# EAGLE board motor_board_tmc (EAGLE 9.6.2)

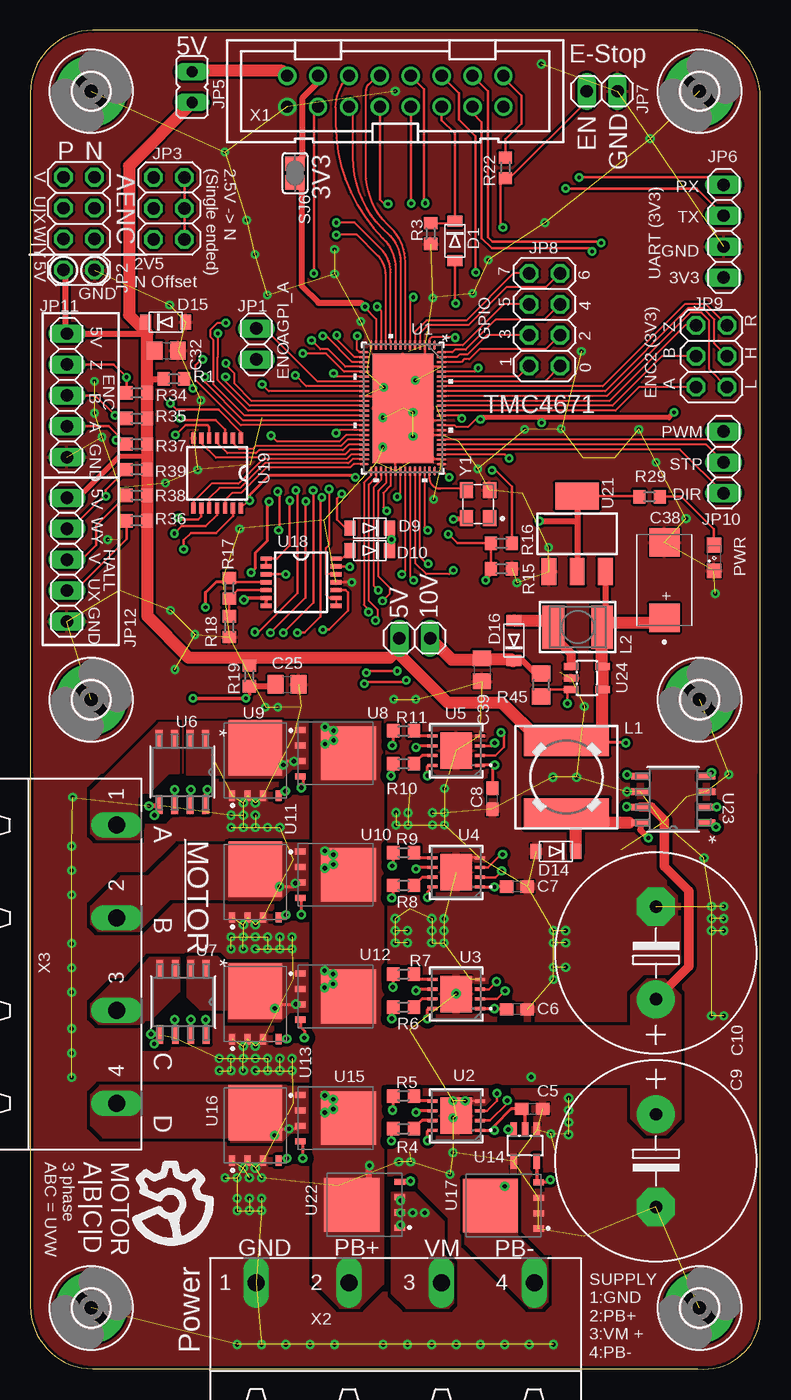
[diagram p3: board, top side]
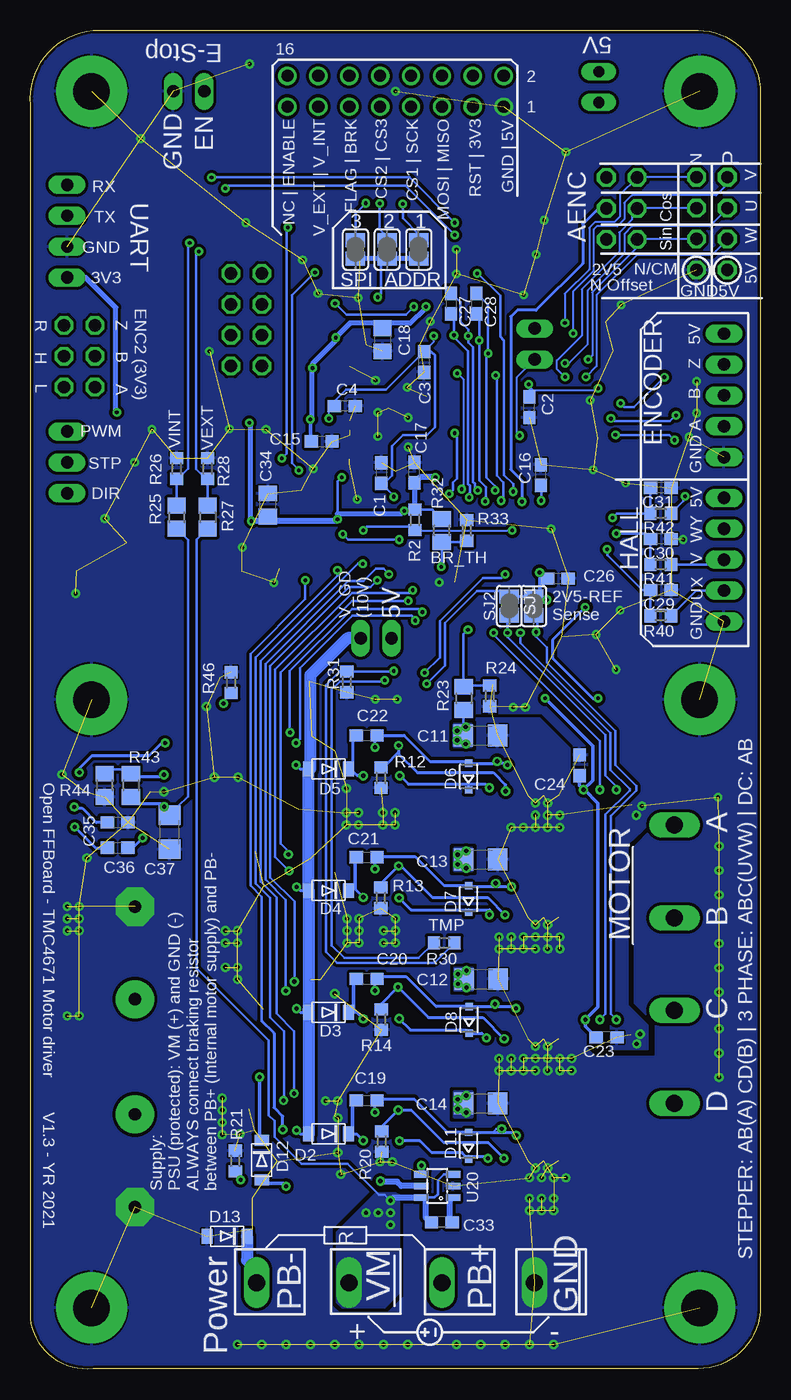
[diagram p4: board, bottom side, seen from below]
Size 60.02 x 110.03 mm. Coordinates in mm from the lower left corner, seen from the top.
Outline: 0,104.91 0,5.15 arc90 5.12,0.03 54.88,0.03 arc90 60,4.15 60,103.91 arc90 54.88,110.03 5.12,110.03 arc90 0,104.91
Copper layers (1*16): Top 0.035mm / dielectric 1.5mm / Bottom 0.035mm
Design rules "jlcpcb *": minimum track width 5mil, minimum drill 0.3mm, track to track 8mil, track to pad 8mil, pad to pad 8mil, via to via 8mil, smd to smd 5mil, copper to edge 0.2mm, drill to drill 8mil, minimum pad ring 10mil, minimum via ring 8mil, stop-mask expansion 4mil, vias tented up to drill 0.4mm, thermal gap 6mil

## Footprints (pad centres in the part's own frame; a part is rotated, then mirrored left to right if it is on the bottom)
C0603 = smd 1.1 x 1: 1 -0.85,0; 2 0.85,0
E7,5-16 = drill 1.016 pad 3.15: + -3.81,0 | drill 1.016 pad 3.15 octagon: - 3.81,0
C1206 = smd 1.6 x 1.8: 1 -1.4,0; 2 1.4,0
C0805 = smd 1.3 x 1.5: 1 -0.95,0; 2 0.95,0
CAPPM7343X310N = smd 2.31 x 2.52: 1 -3.1,0; 2 3.1,0
SOD-123FL = smd 0.91 x 1.22: A 1.637,0; C -1.637,0
SOD323-R = smd 0.6 x 0.6: A 1.1,0; C -1.1,0
3,0-PAD = drill 3 pad 5.842: B3,0 0,0
1X02 = drill 1.016 long: 1 -1.27,0; 2 1.27,0
2X04 = drill 1.016 octagon: 1 -3.81,-1.27; 2 -3.81,1.27; 3 -1.27,-1.27; 4 -1.27,1.27; 5 1.27,-1.27; 6 1.27,1.27; 7 3.81,-1.27; 8 3.81,1.27
2X03 = drill 1.016 octagon: 1 -2.54,-1.27; 2 -2.54,1.27; 3 0,-1.27; 4 0,1.27; 5 2.54,-1.27; 6 2.54,1.27
JP1 = drill 0.914 long: 1 0,-1.27; 2 0,1.27
1X04 = drill 1.016 long: 1 -3.81,0; 2 -1.27,0; 3 1.27,0; 4 3.81,0
1X03 = drill 1.016 long: 1 -2.54,0; 2 0,0; 3 2.54,0
1X05 = drill 1.016 long: 1 -5.08,0; 2 -2.54,0; 3 0,0; 4 2.54,0; 5 5.08,0
8MMINDUCTOR = smd 2.5 x 7: 1 -3,0; 2 3,0
L4532P = smd 1.8 x 3.6: 1 -2,0; 2 2,0
SML0805 = smd 1.2 x 1.2: A 1.05,0; C -1.05,0
R0603 = smd 1 x 1.1: 1 -0.85,0; 2 0.85,0
R0805 = smd 1.3 x 1.5: 1 -0.95,0; 2 0.95,0
SJ = smd 1.168 x 1.6: 1 -0.762,0; 2 0.762,0
QFN76_10P5X6P5 = smd 0.152 x 0.755: 1 -2.6,-5.173; 2 -2.2,-5.173; 3 -1.8,-5.173; 4 -1.4,-5.173; 5 -1,-5.173; 6 -0.6,-5.173; 7 -0.2,-5.173; 8 0.2,-5.173; 9 0.6,-5.173; 10 1,-5.173; 11 1.4,-5.173; 12 1.8,-5.173; 13 2.2,-5.173; 14 2.6,-5.173; 39 2.6,5.173; 40 2.2,5.173; 41 1.8,5.173; 42 1.4,5.173; 43 1,5.173; 44 0.6,5.173; 45 0.2,5.173; 46 -0.2,5.173; 47 -0.6,5.173; 48 -1,5.173; 49 -1.4,5.173; 50 -1.8,5.173; 51 -2.2,5.173; 52 -2.6,5.173 | smd 0.755 x 0.152: 15 3.179,-4.6; 16 3.179,-4.2; 17 3.179,-3.8; 18 3.179,-3.4; 19 3.179,-3; 20 3.179,-2.6; 21 3.179,-2.2; 22 3.179,-1.8; 23 3.179,-1.4; 24 3.179,-1; 25 3.179,-0.6; 26 3.179,-0.2; 27 3.179,0.2; 28 3.179,0.6; 29 3.179,1; 30 3.179,1.4; 31 3.179,1.8; 32 3.179,2.2; 33 3.179,2.6; 34 3.179,3; 35 3.179,3.4; 36 3.179,3.8; 37 3.179,4.2; 38 3.179,4.6; 53 -3.179,4.6; 54 -3.179,4.2; 55 -3.179,3.8; 56 -3.179,3.4; 57 -3.179,3; 58 -3.179,2.6; 59 -3.179,2.2; 60 -3.179,1.8; 61 -3.179,1.4; 62 -3.179,1; 63 -3.179,0.6; 64 -3.179,0.2; 65 -3.179,-0.2; 66 -3.179,-0.6; 67 -3.179,-1; 68 -3.179,-1.4; 69 -3.179,-1.8; 70 -3.179,-2.2; 71 -3.179,-2.6; 72 -3.179,-3; 73 -3.179,-3.4; 74 -3.179,-3.8; 75 -3.179,-4.2; 76 -3.179,-4.6 | smd 5.004 x 8.992: 77 0,0
SDC08A = smd 0.254 x 0.813: 1 -1.2,-1.943; 2 -0.4,-1.943; 3 0.4,-1.943; 4 1.2,-1.943; 5 1.2,1.943; 6 0.4,1.943; 7 -0.4,1.943; 8 -1.2,1.943 | smd 2.997 x 2.591: 9 0,0
SOIC8_D_TEX = smd 1.46 x 0.559: 1 -2.724,1.905; 2 -2.724,0.635; 3 -2.724,-0.635; 4 -2.724,-1.905; 5 2.724,-1.905; 6 2.724,-0.635; 7 2.724,0.635; 8 2.724,1.905
MOSFET_BSC093N04LSGATMA1 = smd 0.5 x 0.85: 1 -1.905,-2.9; 2 -0.635,-2.9; 3 0.635,-2.9; 4 1.905,-2.9 | smd 4.41 x 4.55: 5 0,1.05
SOT23-5L = smd 0.55 x 1.2: 1 -0.95,-1.3; 2 0,-1.3; 3 0.95,-1.3; 4 0.95,1.3; 5 -0.95,1.3
TSSOP14 = smd 0.9 x 0.35: 1 -2.875,1.95; 2 -2.875,1.3; 3 -2.875,0.65; 4 -2.875,0; 5 -2.875,-0.65; 6 -2.875,-1.3; 7 -2.875,-1.95; 8 2.875,-1.95; 9 2.875,-1.3; 10 2.875,-0.65; 11 2.875,0; 12 2.875,0.65; 13 2.875,1.3; 14 2.875,1.95
SOT23-6 = smd 0.55 x 1.2: 1 -0.95,-1.3; 2 0,-1.3; 3 0.95,-1.3; 4 0.95,1.3; 5 0,1.3; 6 -0.95,1.3
SOT223 = smd 1.219 x 2.235: 1 -2.311,-3.099; 2 0,-3.099; 3 2.311,-3.099 | smd 3.6 x 2.2: 4 0,3.099
21-0041B_8_MXM = smd 0.543 x 1.455: 1 -1.905,-2.721; 2 -0.635,-2.721; 3 0.635,-2.721; 4 1.905,-2.721; 5 1.905,2.721; 6 0.635,2.721; 7 -0.635,2.721; 8 -1.905,2.721
PAK100/2500-16 = drill 1 pad 1.422: 1 -8.89,-1.27; 2 -8.89,1.27; 3 -6.35,-1.27; 4 -6.35,1.27; 5 -3.81,-1.27; 6 -3.81,1.27; 7 -1.27,-1.27; 8 -1.27,1.27; 9 1.27,-1.27; 10 1.27,1.27; 11 3.81,-1.27; 12 3.81,1.27; 13 6.35,-1.27; 14 6.35,1.27; 15 8.89,-1.27; 16 8.89,1.27
GMSTBA4 = drill 1.397 long: 1 -11.43,5.08; 2 -3.81,5.08; 3 3.81,5.08; 4 11.43,5.08
ECS-327KE-TR = smd 1.3 x 1.1: 1 -1.15,-0.95; 2 1.15,-0.95; 3 1.15,0.95; 4 -1.15,0.95

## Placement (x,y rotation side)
C1  100nF  [C0603]  31.18,73.65 270 bottom
C2  100nF  [C0603]  19,79.05 90 bottom
C3  100nF  [C0603]  27.65,82.78 90 bottom
C4  100nF  [C0603]  34.17,79.15 180 bottom
C5  100nF  [C0603]  41.25,21.38 180 top
C6  100nF  [C0603]  40,29.58 180 top
C7  100nF  [C0603]  40,39.65 180 top
C8  100nF  [C0603]  37.98,46.88 90 top
C9  680µF  [E7,5-16]  51.42,17.13 270 top
C10  680µF  [E7,5-16]  51.42,34.2 90 top
C11  1µF  [C1206]  23.02,52.08 0 bottom
C12  1µF  [C1206]  22.98,32.05 0 bottom
C13  1µF  [C1206]  23,41.88 0 bottom
C14  1µF  [C1206]  23,21.83 0 bottom
C15  100nF  [C0603]  36.08,76.25 0 bottom
C16  100nF  [C0603]  18.05,73.48 90 bottom
C17  100nF  [C0603]  28.45,73.68 90 bottom
C18  4.7µF  [C0805]  31.07,84.6 270 bottom
C19  100nF  [C0603]  32.38,22.08 0 bottom
C20  100nF  [C0603]  32.38,32.08 0 bottom
C21  100nF  [C0603]  32.38,42.08 0 bottom
C22  100nF  [C0603]  32.38,52.08 0 bottom
C23  100nF  [C0603]  12.65,27.28 180 bottom
C24  100nF  [C0603]  14.88,49.63 90 bottom
C25  4.7µF  [C0805]  21.1,56.28 0 top
C26  100n  [C0603]  16.65,64.98 0 bottom
C27  1n  [C0603]  25.45,87.58 270 bottom
C28  1n  [C0603]  23.35,87.58 270 bottom
C29  1n  [C0603]  8.2,64.03 180 bottom
C30  1n  [C0603]  8.2,68.23 180 bottom
C31  1n  [C0603]  8.2,72.43 180 bottom
C32  4.7µF  [C0805]  11.18,83.7 0 top
C33  100nF  [C0603]  26.2,12.08 180 bottom
C34  4.7µF  [C0805]  40.5,71.03 90 bottom
C35  100nF  [C0603]  52.85,44.93 180 bottom
C36  100nF  [C0603]  52.85,42.85 0 bottom
C37  1µF  [C1206]  48.58,44.13 90 bottom
C38  593D476X0016D2TE3  [CAPPM7343X310N]  52.12,64.85 90 top
C39  4.7µF  [C0805]  37.12,57.48 270 top
D1  LV low drop  [SOD-123FL]  34.9,92.73 270 top
D2  HV >100V  [SOD-123FL]  35.5,19.33 180 bottom
D3  HV >100V  [SOD-123FL]  35.5,29.33 180 bottom
D4  HV >100V  [SOD-123FL]  35.5,39.33 180 bottom
D5  HV >100V  [SOD-123FL]  35.5,49.33 180 bottom
D6  BZX384-XXX  [SOD323-R]  24,48.7 90 bottom
D7  BZX384-XXX  [SOD323-R]  24,38.63 90 bottom
D8  BZX384-XXX  [SOD323-R]  23.95,28.7 90 bottom
D9  LV low drop  [SOD-123FL]  27.9,69.13 180 top
D10  LV low drop  [SOD-123FL]  27.9,67.28 180 top
D11  BZX384-XXX  [SOD323-R]  24,18.35 90 bottom
D12  HV >100V  [SOD-123FL]  41,17.18 270 bottom
D13  Zener 65V (MMSZ5265BT1G)  [SOD-123FL]  43.85,10.93 180 bottom
D14  HV >100V  [SOD-123FL]  43.2,42.55 180 top
D15  5.6V zener  [SOD-123FL]  11.12,86.05 0 top
D16  LV low drop  [SOD-123FL]  39.75,59.88 90 top
H1  MOUNT-PAD-ROUND3.0  [3,0-PAD]  55,5.03 0 top
H2  MOUNT-PAD-ROUND3.0  [3,0-PAD]  5,5.03 0 top
H3  MOUNT-PAD-ROUND3.0  [3,0-PAD]  55,105.03 0 top
H4  MOUNT-PAD-ROUND3.0  [3,0-PAD]  55,55.03 0 top
H5  MOUNT-PAD-ROUND3.0  [3,0-PAD]  5,105.03 0 top
H6  MOUNT-PAD-ROUND3.0  [3,0-PAD]  5,55.03 0 top
JP1  [1X02]  18.57,84.25 90 top
JP2  [2X04]  4,94.15 90 top
JP3  [2X03]  11.4,95.4 270 top
JP4  V_DRV  [1X02]  31.6,60.08 180 top
JP5  5V  [JP1]  13.3,105.38 180 top
JP6  [1X04]  57,93.53 270 top
JP7  [1X02]  47,105.03 180 top
JP8  [2X04]  42.27,86.25 90 top
JP9  [2X03]  56,83.25 90 top
JP10  [1X03]  57,74.53 270 top
JP11  [1X05]  3,80.03 270 top
JP12  [1X05]  3,66.53 270 top
L1  220µH  [8MMINDUCTOR]  44.08,48.65 90 top
L2  10µH  [L4532P]  45,60.98 180 top
LED1  Green  [SML0805]  56.2,66.68 90 top
R1  2.2  [R0603]  11.8,81.38 180 top
R2  10k  [R0603]  28.4,69.8 90 bottom
R3  10k  [R0603]  32.9,93.33 90 top
R4  2.2  [R0603]  30.68,19.75 0 top
R5  2.2  [R0603]  30.68,22.45 0 top
R6  2.2  [R0603]  30.68,29.75 0 top
R7  2.2  [R0603]  30.68,32.45 0 top
R8  2.2  [R0603]  30.68,39.75 0 top
R9  2.2  [R0603]  30.68,42.45 0 top
R10  2.2  [R0603]  30.68,49.75 0 top
R11  2.2  [R0603]  30.68,52.45 0 top
R12  33k  [R0603]  31.2,48.6 90 bottom
R13  33k  [R0603]  31.23,38.73 90 bottom
R14  33k  [R0603]  31.18,28.73 90 bottom
R15  10k  [R0603]  38.73,65.78 180 top
R16  1.5k  [R0603]  38.73,67.88 180 top
R17  10k  [R0603]  16.35,64.18 90 top
R18  10k  [R0603]  16.35,61.03 90 top
R19  2.2  [R0603]  18,56.98 90 top
R20  33k  [R0603]  31.15,18.7 90 bottom
R21  33k  [R0603]  43.17,17.1 270 bottom
R22  1.5k  [R0603]  39.05,98.73 90 top
R23  71.5k  [R0805]  24.4,55.13 270 bottom
R24  1.5k  [R0603]  22.25,55.33 90 bottom
R25  294k  [R0805]  48,70.03 270 bottom
R26  10k  [R0603]  48,74.03 270 bottom
R27  294k  [R0805]  45.45,70.03 270 bottom
R28  10k  [R0603]  45.45,74.03 270 bottom
R29  1.5k  [R0603]  50.9,71.7 180 top
R30  10k thermistor  [R0603]  26,35.03 180 bottom
R31  1.5k  [R0603]  34,56.48 90 bottom
R32  71.5k  [R0805]  26.2,68.93 90 bottom
R33  47k  [R0603]  24.15,68.93 270 bottom
R34  4.7k  [R0603]  8.75,80.23 0 top
R35  4.7k  [R0603]  8.75,78.13 0 top
R36  4.7k  [R0603]  8.75,69.73 0 top
R37  4.7k  [R0603]  8.75,76.03 0 top
R38  4.7k  [R0603]  8.75,71.83 0 top
R39  4.7k  [R0603]  8.75,73.93 0 top
R40  1.5k  [R0603]  8.2,61.93 0 bottom
R41  1.5k  [R0603]  8.2,66.13 0 bottom
R42  1.5k  [R0603]  8.2,70.33 0 bottom
R43  294k  [R0805]  51.75,47.98 270 bottom
R44  71.5k  [R0805]  53.92,47.98 270 bottom
R45  71.5k  [R0805]  42,56.23 90 top
R46  10k  [R0603]  43.52,56.43 270 bottom
SJ1  [SJ]  20.65,62.73 270 bottom
SJ2  [SJ]  18.65,62.73 270 bottom
SJ3  [SJ]  28.1,92.03 270 bottom
SJ4  [SJ]  30.7,92.03 270 bottom
SJ5  [SJ]  33.3,92.03 270 bottom
SJ6  3.3V  [SJ]  21.75,98.3 270 top
U1  TMC4671  [QFN76_10P5X6P5]  30.62,78.98 180 top
U2  LM5109BSD  [SDC08A]  35,20.83 90 top
U3  LM5109BSD  [SDC08A]  35,30.83 90 top
U4  LM5109BSD  [SDC08A]  35,40.83 90 top
U5  LM5109BSD  [SDC08A]  35,50.83 90 top
U6  TMCS1100  [SOIC8_D_TEX]  12.5,49.08 270 top
U7  TMCS1100  [SOIC8_D_TEX]  12.55,30.18 270 top
U8  BSC030N08NS5ATMA1  [MOSFET_BSC093N04LSGATMA1]  25.1,50.63 270 top
U9  BSC030N08NS5ATMA1  [MOSFET_BSC093N04LSGATMA1]  18.5,50.03 0 top
U10  BSC030N08NS5ATMA1  [MOSFET_BSC093N04LSGATMA1]  25.1,40.63 270 top
U11  BSC030N08NS5ATMA1  [MOSFET_BSC093N04LSGATMA1]  18.5,40.03 0 top
U12  BSC030N08NS5ATMA1  [MOSFET_BSC093N04LSGATMA1]  25.1,30.63 270 top
U13  BSC030N08NS5ATMA1  [MOSFET_BSC093N04LSGATMA1]  18.5,30.03 0 top
U14  MCP14XX  [SOT23-5L]  40.67,18.38 180 top
U15  BSC030N08NS5ATMA1  [MOSFET_BSC093N04LSGATMA1]  25.1,20.63 270 top
U16  BSC030N08NS5ATMA1  [MOSFET_BSC093N04LSGATMA1]  18.5,20.03 0 top
U17  BSC030N08NS5ATMA1  [MOSFET_BSC093N04LSGATMA1]  38.88,13.45 90 top
U18  MCP6004  [TSSOP14]  22.25,64.68 0 top
U19  74LV17APWJ  [TSSOP14]  15.35,73.63 270 top
U20  LM74700-Q1  [SOT23-6]  26.57,15.05 90 bottom
U21  [SOT223]  44.95,68.65 0 top
U22  BSC030N08NS5ATMA1  [MOSFET_BSC093N04LSGATMA1]  27.48,13.5 90 top
U23  MAX5033BASA+T  [21-0041B_8_MXM]  52.85,46.83 90 top
U24  AP3012KTR-G1  [SOT23-5L]  45.75,56.8 270 top
X1  2516-  [PAK100/2500-16]  30,105.03 0 top
X2  GMSTBA4  [GMSTBA4]  30,2.03 0 top
X3  GMSTBA4  [GMSTBA4]  2,33.28 270 top
Y1  25MHz  [ECS-327KE-TR]  36.8,71.1 90 top

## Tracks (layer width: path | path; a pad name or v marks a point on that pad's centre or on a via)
2.5V_REF  (via drill 0.3, 0.35)
  Top 0.2: JP3.2 JP3.4 JP3.6 | v27.45,56.33 27.6,56.48 30.75,56.48 v30.9,56.63
  Top 0.254: v18.15,65.48 18.47,65.8 18.47,67.08 19.47,68.07 19.47,71.16 v19.62,71.31
  Top 0.305: U18.7 U18.6 17.7,63.38 v17.55,63.23
  Bottom 0.2: SJ2.1 SJ1.1 21.1,63.94 23.32,63.94 25.95,61.31 25.95,57.83 v27.45,56.33 | SJ2.1 18.39,63.23 | R30.2 28.1,33.78 34.2,33.78 35.25,34.83 35.25,55.86 34.58,56.52 31,56.52 v30.9,56.63 | 18.15,63.99 SJ2.1 | C26.1 18,65.48 v18.15,65.48
  Bottom 0.254: JP3.4 12.82,95.55 13.16,95.55 14.61,94.11 14.61,90.88 18.46,87.03 20,87.03 20.52,86.5 20.52,73.94 19.62,73.04 v19.62,71.31
  Bottom 0.305: 18.39,63.23 v17.55,63.23 | v18.15,65.48 18.15,63.99
2.5V_REF_A  (via drill 0.3, 0.35)
  Top 0.152: U1.17 26.44,82.78 24.29,84.93 v24.02,84.93
  Top 0.2: 11.87,47.61 v11.85,47.63 | v23.24,72.23 23.29,72.18 23.29,63.01 v20.8,60.53
  Top 0.254: U6.6 11.87,47.61
  Bottom 0.2: v11.85,47.63 11.85,47.88 12.75,48.78 12.75,52.13 20.8,60.18 v20.8,60.53 20.8,61.81 SJ1.2 | v23.24,72.23 23.49,72.48 23.49,72.77 23.64,72.92 23.64,83.99 24.02,84.37 v24.02,84.93 24.02,85.45 24.65,86.07 24.65,87.7 25.37,88.43 C27.1
2.5V_REF_C  (via drill 0.3, 0.35)
  Top 0.152: U1.19 25.8,81.98 24.3,83.47 v22.4,83.47
  Top 0.2: v21.82,72.22 21.97,72.07 21.97,63.8 18.75,60.58 v18.45,60.58
  Top 0.254: U7.6 11.91,28.66 v11.85,28.73
  Bottom 0.2: v11.85,28.73 12.3,29.18 12.3,45.45 10.2,47.55 10.2,47.93 11.94,49.67 11.94,52.46 17.55,58.07 17.55,59.33 18.45,60.23 v18.45,60.58 18.35,60.68 18.35,61.66 SJ2.2 | v21.82,72.22 21.82,72.56 22.54,73.28 22.54,83.34 v22.4,83.47 22.4,87.48 C28.1
2.5V_REF_RAW
  Top 0.2: U18.5 17.05,64.03 R17.1 R18.2
5V_ADC  (via drill 0.3)
  Top 0.152: U1.23 19.6,80.38 v19.05,80.93
  Top 0.2: R1.1 12.65,81.32 v13.34,80.62
  Bottom 0.152: C2.2 19,80.88 v19.05,80.93 19.05,80.78 18.74,80.47 13.49,80.47 v13.34,80.62
5V_SENSE  (via drill 0.3, 0.35)
  Top 0.2: U18.4 16.35,64.68 R17.2 16.05,64.73
  Top 0.254: 16.05,64.73 15.3,64.73 14.4,63.83 v14.4,62.63 | v14.55,47.63 14.4,47.48 U6.8 | v14.4,28.73 14.46,28.67 U7.8
  Top 0.3: v13.35,55.13 v17.7,55.13 18,55.43 R19.1
  Top 0.5: R19.1 20,56.13 C25.1
  Bottom 0.2: v14.55,47.63 14.47,47.63
  Bottom 0.254: v13.35,55.13 13.8,55.13 17.1,58.43 17.1,59.93 v14.4,62.63
  Bottom 0.3: v17.7,55.13 13.8,51.23 13.8,48.38 v14.55,47.63 14.88,47.95 C24.1 | C23.2 14.4,28.18 v14.4,28.73 13.35,29.78 13.35,46.5 14.47,47.63
+3V3  (via drill 0.3, 0.35)
  Top 0.152: U1.52 33.25,73.78 33.95,73.78 v34.42,73.3 | U1.43 29.62,72.6 29.02,72 29.02,70.83 v29.3,70.55 | U1.13 28.42,86.3 27.5,87.22 v27.5,87.33 | v34.92,84.78 34.92,84.83 33,84.83 32.82,84.65 U1.2 | v36.83,82.28 36.52,81.98 U1.72 | v37,78.05 36.6,78.05 35.99,77.44 35,77.44 34.87,77.58 U1.61
  Top 0.2: U21.4 50,71.75 R29.2 | U19.14 17.93,71.38 v18.02,71.38
  Top 0.254: v26.73,73.3 26.57,73.45 19.64,73.45 18.02,71.83 v18.02,71.38
  Top 0.4: Y1.4 35.75,69.85 v34.77,69.85 | v52.92,78.63 52.5,78.2 42.05,78.2 | 42.05,78.2 37.15,78.2 v37,78.05 | v42.02,77.78 42.02,78.18 42.05,78.2
  Top 0.5: v27.5,87.33 27.18,87.65 23.68,87.65 22.3,89.03 22.3,96.99 SJ6.2 | U21.4 44.95,69.7 | v41.85,69.7 44.95,69.7 | 44.95,69.7 U21.2
  Bottom 0.2: v29.3,70.55 29.2,70.65 R2.2 26.98,70.65 R32.2 | C34.1 40.88,69.7 v41.85,69.7 | v34.42,73.3 34.77,72.95 v34.77,69.85 | C15.1 37,76.33 | C16.1 18.02,72.6 v18.02,71.38
  Bottom 0.3: v27.5,87.33 27.6,87.23 | 36.91,78.15 v37,78.05 37,76.33 | v34.77,69.85 34.77,69.73
  Bottom 0.4: v34.77,69.85 34.77,70.3 29.55,70.3 v29.3,70.55 28.93,70.55 28.45,71.03 C17.1 | 27.6,87.23 27.6,87.13 28.77,85.95 31.07,85.95 | 36.91,78.15 36.91,82.2 v36.83,82.28 36.83,82.63 34.92,84.53 v34.92,84.78 33.73,85.98 31.07,85.98 31.07,85.95 | v52.92,78.63 53,78.7 53,87.25 55.47,89.72 JP6.4 | v42.02,77.78 41.98,77.73 41.98,69.83 v41.85,69.7 | C18.1 31.07,85.95
  Bottom 0.5: v41.85,69.7 41.83,69.73 34.77,69.73 | v26.73,73.3 27.98,73.3 C17.1
+5V  (via drill 0.35)
  Top 0.152: R34.2 9.6,80.88
  Top 0.2: 56,48.84 55.9,48.73 U23.4 | v48.95,51.45 48.91,51.49 | 47.54,51.49 47.38,51.65 L1.2 | D15.C 9.49,85.51 9.35,85.38 | 18,58.46 R19.2
  Top 0.254: v56,49.03 56,48.84 | 48.91,51.49 47.54,51.49
  Top 0.4: JP12.1 3.88,71.61 7.33,75.05 9.6,75.05
  Top 0.5: 9.6,85.13 9.58,85.11 JP11.1 2.88,85.23 2.88,90.2 JP2.2 | U24.4 47,55.8 | 47,52.03 46.62,51.65 L1.2 | 9.6,81.03 9.95,81.38 R1.2
  Top 0.508: U21.3 47.26,61.24 L2.1
  Top 0.8: U24.5 47,57.8
  Top 1: U24.4 U24.5 | 9.6,83.08 9.6,81.03 R34.2 R35.2 R37.2 9.6,75.05 R39.2 R38.2 R36.2 9.6,61.88 13.01,58.46 18,58.46 29.54,58.46 30.33,59.25 JP4.2 30.33,58.75 34.33,54.75 38.77,54.75 41.88,51.65 L1.2 | 9.6,83.08 9.6,85.13 9.35,85.38 8.1,86.63 8.1,98.91 JP5.2 | 47,55.8 47,52.03 | C32.1 9.6,83.08 | C38.1 51.67,61.3 47.33,61.3 L2.1 47,57.8
  Bottom 0.254: v56,49.03 56,49.38 54.95,50.43 50.27,50.43 49.25,51.45 v48.95,51.45
AENC_UX  (via drill 0.3)
  Top 0.15: 18.2,79.58 16.75,81.03 16.75,81.85 16.07,82.53 v16.07,82.68
  Top 0.152: U1.25 18.2,79.58
  Bottom 0.15: 14.22,88.65 14.22,84.2 15.75,82.68 v16.07,82.68
  Bottom 0.152: 14.22,88.65 11.19,91.69 11.19,93.29 10.56,93.93 4.17,93.93 2.73,95.37 JP2.6
AENC_UX_N  (via drill 0.3)
  Top 0.15: U1.26 18.02,79.18 16.05,81.15 v16.05,81.55
  Bottom 0.152: v16.05,81.55 16.1,81.55 16.75,82.2 16.75,82.9 14.7,84.95 14.7,88.75 11.61,91.84 11.61,93.42 10.58,94.45 10.58,94.95 JP3.3 10.11,95.42 JP2.5
AENC_VN  (via drill 0.3)
  Top 0.15: U1.27 17.91,78.78
  Top 0.152: 17.91,78.78 15.39,81.29 15.39,83.17 15.41,83.18 v15.41,85.13
  Bottom 0.152: 2.72,97.41 3.65,96.48 10.57,96.48 11.2,95.85 11.2,94.5 11.78,93.92 13.46,93.92 13.72,93.65 13.72,90.23 15.41,88.55 v15.41,85.13
  Bottom 0.2: JP2.8 2.72,97.95 2.72,97.41
AENC_VN_N  (via drill 0.3)
  Top 0.15: U1.28 17.62,78.38 15.04,80.96
  Top 0.152: v16.08,85.98 15.36,85.98 14.78,85.4 14.78,84.87 15.04,84.61 15.04,80.96
  Bottom 0.152: v16.08,85.98 16.08,88.38 14.08,90.38 14.08,93.8 13.61,94.27 12.01,94.27 11.56,94.72 11.56,96.52 JP3.1 10.11,97.96 JP2.7
AENC_WY  (via drill 0.3)
  Top 0.15: U1.29 17.48,77.98 14.35,81.11 v14.35,81.55
  Bottom 0.152: v14.35,81.55 13.47,82.43 13.47,88.25 10.18,91.55 4,91.55 2.73,92.83 JP2.4
AENC_WY_N  (via drill 0.3)
  Top 0.15: U1.30 17.28,77.58 13.57,81.28 13.57,82.53
  Top 0.152: 13.57,82.53 14.03,82.98 v14.17,82.98
  Bottom 0.152: v14.17,82.98 13.83,83.31 13.83,88.5 10.13,92.2 JP3.5 10.11,92.88 JP2.3
AGPI_A
  Top 0.152: U1.21 23.6,81.18 19.25,85.52 JP1.2
AGPI_B  (via drill 0.3)
  Top 0.152: U1.22 22.68,80.78 v21.78,81.68
  Top 0.2: U18.2 U18.1 20.27,66.63 21.32,67.67 v21.32,71.38
  Bottom 0.2: v21.78,81.68 21.68,81.58 21.68,73.43 21.12,72.86 21.12,71.58 v21.32,71.38
BRAKE_CTRL  (via drill 0.3, 0.35)
  Top 0.2: D10.C 29.69,67.43 v29.69,68.18 29.69,69.15 29.56,69.15 D9.C | v34.35,68.63 35.1,67.88 R16.2 R15.2 37.88,65.28 v37.42,64.83
  Top 0.254: U14.3 v39.27,19.68
  Bottom 0.2: 41,28.63 41,38.82 41.92,39.73 41.92,58.79 37.42,63.28 v37.42,64.83 | v34.35,68.63 33.9,68.18 v29.69,68.18
  Bottom 0.254: v39.27,19.68 39.27,20.78 40,21.5 40,27.63 41,28.63
BRAKE_CTRL_EXT  (via drill 0.3)
  Top 0.2: X1.12 35.25,104.86 35.25,102.68 36.6,101.33 36.6,90.18 v36.62,90.15 | R16.1 39.58,72.55 38.25,73.88 v37.95,73.88
  Bottom 0.2: v36.62,90.15 38.52,88.26 38.52,74.45 v37.95,73.88
BRAKE_CTRL_TMC  (via drill 0.3)
  Top 0.152: U1.31 25.38,77.18 v25.12,76.93
  Top 0.2: v25.6,71.95 25.2,71.55 25.2,69.83 25.9,69.13 D9.A
  Bottom 0.2: v25.12,76.93 24.95,76.75 24.95,73.2 25.3,72.85 25.3,72.25 v25.6,71.95
BRAKE_GATE  (via drill 0.35)
  Top 0.254: v42.75,15.55 42.55,15.36 U17.4
  Top 0.3: U17.4 41.65,15.48 41.65,17.05 U14.5
  Bottom 0.2: R21.2 42.75,16.25 v42.75,15.55
BRAKE_RES_COMP
  Top 0.152: D10.A 25.61,66.63 U18.14
BRAKE_RES_TH  (via drill 0.3)
  Top 0.2: U18.13 26.2,65.98 v26.25,65.93
  Bottom 0.2: R33.2 24.25,67.98 R32.1 26.2,65.98 v26.25,65.93
C_HS_A  (via drill 0.3, 0.35)
  Top 0.152: U1.39 28.02,73.45 27.42,72.85 27.42,62.8 27.79,62.43 v27.79,62.23
  Top 0.2: U5.2 38.23,50.43 38.92,51.13 38.92,52.08 v38.67,52.33
  Bottom 0.2: v38.67,52.33 38.7,52.35 38.7,57.37 33.59,62.48 28.12,62.48 27.87,62.23 v27.79,62.23
C_HS_B  (via drill 0.3, 0.35)
  Top 0.152: U1.41 28.82,73.05 28.22,72.45 28.22,64.41 v28.6,64.03
  Top 0.2: U4.2 38.23,40.43 v38.75,40.95
  Bottom 0.2: v38.75,40.95 39.9,42.1 39.9,57.5 33.6,63.8 28.82,63.8 v28.6,64.03
C_HS_C  (via drill 0.3, 0.35)
  Top 0.152: U1.46 30.8,73.78 30.8,65.58 v30.55,65.33
  Top 0.2: U3.2 38.38,30.43 v39.02,31.08
  Bottom 0.2: v39.02,31.08 39.02,38.55 40.71,40.23 40.71,57.97 33.91,64.76 32.64,64.76 31.62,65.78 31,65.78 v30.55,65.33
C_HS_D  (via drill 0.3, 0.35)
  Top 0.152: v34.77,65.65 34.45,65.33 32.55,65.33 31.62,66.26 U1.48
  Top 0.2: U2.2 37.77,20.43 39.2,21.85 v39.2,22.08
  Bottom 0.2: v39.2,22.08 39.15,22.13 39.15,27.75 40.33,28.93 40.33,38.71 41.51,39.9 41.51,58.49 34.77,65.23 v34.77,65.65
C_LS_A  (via drill 0.3, 0.35)
  Top 0.152: U1.40 28.42,73.3 27.82,72.7 27.82,63.13 28.52,62.43 28.52,61.68 v28.38,61.53
  Top 0.2: U5.3 37.95,51.23 v38.17,51.45
  Bottom 0.2: v38.17,51.45 37.85,51.78 37.85,57.63 33.52,61.95 28.68,61.95 28.38,61.65 v28.38,61.53
C_LS_B  (via drill 0.3, 0.35)
  Top 0.152: U1.42 29.22,72.8 28.62,72.2 28.62,65.13 29.56,64.19 29.56,63.74 v28.95,63.13
  Top 0.2: U4.3 37.62,41.23 38.7,42.3 v38.83,42.3
  Bottom 0.2: v38.83,42.3 38.83,42.58 39.45,43.2 39.45,57.25 33.57,63.13 v28.95,63.13
C_LS_C  (via drill 0.3, 0.35)
  Top 0.152: U1.47 31.22,65.11 v31.5,64.83
  Top 0.2: U3.3 37.7,31.23 v38.33,31.85
  Bottom 0.2: v38.33,31.85 38.33,38.42 40.3,40.4 40.3,57.8 33.82,64.28 32.05,64.28 v31.5,64.83
C_LS_D  (via drill 0.3, 0.35)
  Top 0.152: U1.49 32,73.78 32,66.78 32.58,66.2 v32.7,66.2
  Top 0.2: v38.35,22.65 38.35,22.05 37.52,21.23 U2.3
  Bottom 0.2: v38.35,22.65 38.35,27.78 39.8,29.23 39.8,38.76 41.11,40.07 41.11,58.19 33.1,66.2 v32.7,66.2
CLK_25M
  Top 0.152: Y1.3 35.75,72.35 33.7,72.35 arc-90 32.82,73.23 U1.51
CS1  (via drill 0.3)
  Top 0.2: X1.7 28.73,96.12 29.1,95.75 v29.4,95.75
  Bottom 0.2: SJ3.1 28.1,93.29 29.4,94.59 v29.4,95.75
CS2  (via drill 0.3)
  Top 0.2: X1.9 31.27,95.84 v31.3,95.81
  Bottom 0.2: v31.3,95.81 31.3,93.71 30.7,93.11 SJ4.1
CS3  (via drill 0.3)
  Top 0.2: X1.10 32.38,105.19 32.38,95.8 32.42,95.8 v32.45,95.83
  Bottom 0.2: SJ5.1 33.3,94.98 v32.45,95.83
CS_TMC  (via drill 0.3)
  Top 0.152: 31.43,88.1 31.22,87.9 U1.6
  Top 0.2: v31.48,88.1 31.43,88.1
  Bottom 0.2: v31.48,88.1 31.2,88.38 31.2,90.76 SJ4.2
  Bottom 0.4: SJ3.2 SJ4.2 SJ5.2
DIR
  Top 0.152: JP10.3 53.41,75.58 U1.56
ENABLE  (via drill 0.3)
  Top 0.152: 39.02,75.18 U1.55
  Top 0.2: v39.35,74.84 39.02,75.18 | v38.85,93.82 38.62,94.05 38.62,97.45 R22.1 39.4,97.88 45.73,104.21 JP7.2
  Bottom 0.2: v38.85,93.82 38.95,93.72 38.95,75.24 v39.35,74.84
ENC2_A
  Top 0.152: JP9.2 50.03,80.71 48.09,78.78 U1.64
ENC2_B
  Top 0.152: JP9.4 51.93,83.25 47.85,79.18 U1.65
ENC2_Z
  Top 0.152: JP9.6 53.83,85.79 47.62,79.58 U1.66
ENC_A
  Top 0.152: U1.35 26.26,75.58 25.85,75.17 18.98,75.17 18.73,74.91 15.26,74.91 14.05,76.12 U19.6
ENC_A_5V  (via drill 0.3)
  Top 0.152: v7.05,76.35 7.58,76.35 R37.1
  Top 0.2: R37.1 6.44,77.49 JP11.4 | U19.5 14.7,77.44 14.55,77.59 12.77,77.59 11.95,76.78 v11.93,76.78
  Bottom 0.2: v7.05,76.35 7.47,76.78 v11.93,76.78
ENC_B
  Top 0.152: U1.34 26.16,75.98 25.7,75.52 18.8,75.52 18.55,75.27 16.2,75.27 15.35,76.12 U19.4
ENC_B_5V  (via drill 0.3)
  Top 0.2: R35.1 7.22,78.13 v6.95,78.4 5.33,80.03 JP11.3 | U19.3 16,77.21 15.21,77.99 12.3,77.99 v12.3,78.13
  Bottom 0.2: v6.95,78.4 7.45,77.9 12.07,77.9 v12.3,78.13
ENC_Z
  Top 0.152: U1.33 26.05,76.38 25.55,75.88 18.53,75.88 18.27,75.62 17.15,75.62 16.65,76.12 U19.2
ENC_Z_5V  (via drill 0.3)
  Top 0.2: JP11.2 6.86,82.57 v7.9,81.53 R34.1 | U19.1 17.3,77.02 15.48,78.85 12.03,78.85 v11.5,79.38
  Bottom 0.2: v11.5,79.38 11.2,79.08 10.4,79.08 7.92,81.55 v7.9,81.53
ENO  (via drill 0.3)
  Top 0.152: U1.32 25.95,76.78 25.41,76.23 20.28,76.23 v19.79,76.73
  Bottom 0.152: JP1.1 20.05,81.51 20.05,76.99 v19.79,76.73
FLAG
  Top 0.152: R3.2 34.85,94.18 34.9,94.23 D1.C
  Top 0.2: X1.11 33.81,102.66 34.9,101.57 D1.C
G_HS_A  (via drill 0.35)
  Top 0.254: v22.27,47.78 22.48,47.78 22.48,48.45 U8.4 | R10.1 29.82,48.95 v29.65,48.78
  Bottom 0.2: D6.C 24,48.08
  Bottom 0.254: v22.27,47.78 22.57,48.08 24,48.08 28.95,48.08 v29.65,48.78
G_HS_B  (via drill 0.35)
  Top 0.254: v22.27,37.35 22.27,38.65 U10.4 | R8.1 29.82,38.85 v29.7,38.73
  Bottom 0.2: D7.C 24,37.75
  Bottom 0.254: 24,37.75 22.27,37.75 v22.27,37.35 | v29.7,38.73 28.73,37.75 24.23,37.75 D7.C
G_HS_C  (via drill 0.35)
  Top 0.254: U12.4 22.2,28.13 22.52,27.8 v22.52,27.23 | v29.7,28.8 29.82,28.93 R6.1
  Bottom 0.254: v22.52,27.23 22.9,27.6 D8.C 24.23,27.88 28.77,27.88 v29.7,28.8
G_HS_D  (via drill 0.35)
  Top 0.254: v22.4,17.33 22.4,18.52 U15.4 | v29.68,18.75 29.68,19.6 R4.1
  Bottom 0.2: D11.C 24,17.5
  Bottom 0.254: 24,17.5 22.45,17.5 22.4,17.45 v22.4,17.33 | D11.C 24.52,17.78 27.02,17.78 28,18.75 v29.68,18.75
G_LS_A  (via drill 0.35)
  Top 0.254: U9.4 20.57,47.13 v20.95,47.5 | R11.1 29.82,51.33 v29.75,51.25
  Bottom 0.152: R12.2 31.02,49.45 30.73,49.75
  Bottom 0.254: v20.95,47.5 20.95,48.01 21.97,49.03 28.21,49.03 29.75,50.58 | v29.75,51.25 29.75,50.58 | 29.75,50.58 29.82,50.65 30.73,49.75
G_LS_B  (via drill 0.35)
  Top 0.254: U11.4 20.8,37.13 v21,37.33 | R9.1 29.82,41.43 v29.75,41.35
  Bottom 0.152: R13.2 31.04,39.76 31.04,40.06
  Bottom 0.254: v21,37.33 22.43,38.75 26.95,38.75 29.55,41.35 v29.75,41.35 31.04,40.06
G_LS_C  (via drill 0.35)
  Top 0.254: U13.4 20.43,27.15 v21.07,27.15 | R7.1 29.82,31.42 v29.8,31.39
  Bottom 0.152: R14.2 31.18,30.02
  Bottom 0.254: v21.07,27.15 22.82,28.9 27.31,28.9 v29.8,31.39 31.18,30.02
G_LS_D  (via drill 0.35)
  Top 0.254: v21.1,17.33 20.61,17.33 U16.4 | R5.1 29.82,21.34 v29.77,21.29
  Bottom 0.152: R20.2 31.15,19.92
  Bottom 0.254: v21.1,17.33 22.4,18.63 26.05,18.63 28.72,21.29 v29.77,21.29 31.15,19.92
GND  (via drill 0.3, 0.35)  (275 unrouted)
  Top 0.152: 30.62,80.03 30.62,81.9 31.1,82.38 32.5,82.38 | 30.62,80.03 U1.77 | U1.24 29,79.98 | 29,79.98 30.57,79.98 30.62,80.03 | U1.54 33.25,74.78 31.5,76.52 | 31.42,76.78 31.59,76.61 31.5,76.52 | 31.42,76.78 30.62,77.58 30.62,78.03 | 30.62,78.03 U1.77 | U1.62 32.55,77.98 32.5,78.03 30.62,78.03 | U1.73 32.5,82.38 | U1.3 32.42,82.46 32.5,82.38 | U1.77 30,78.98 29,79.98 | U1.44 30.02,75.01 30,75.03 31.5,76.52 | U1.59 31.42,76.78
  Top 0.2: U2.4 36.92,22.05 v35.75,22.05 | U4.4 36.92,42.05 35.75,42.05 35,41.3 U4.9 | U5.4 36.92,52.05 | 36.16,32.03 35,30.87 U3.9 | U18.11 v26.43,64.68
  Top 0.4: v10.2,45.53 10.6,45.92 U6.5 10.51,46.44 10.35,46.28 v9.75,46.28 | v10.18,26.73 10.64,27.2 U7.5 10.57,27.53 v9.9,27.53
  other vias: 19.5,25.53 18.5,25.53 17.5,25.53 16.5,25.53 16.5,24.53 17.5,24.53 19.5,24.53 18.5,24.53 16,100.03 30,105.03 25,92.03 36.38,88.4 42.3,94.23 42,107.28 25,90.03 29.05,80.68 19,13.03 17,13.03 50.95,101.13 11.45,87.48 15.53,24.53 17.5,26.53 18.5,26.53 36.77,74 51.45,74.53 17.77,94.43 13.75,73.93 45.3,83.65 31.65,81.28 28.98,78.2 31.45,78.63 28.98,75.78 31.45,76.68 19,15.73 18,15.73 17,15.73 16,15.73 17.5,16.53 18.5,16.53 19.5,35.53 18.5,35.53 17.5,35.53 16.5,35.53 16.5,34.53 17.5,34.53 19.5,34.53 18.5,34.53 17.5,36.53 18.5,36.53 18.5,45.53 17.5,45.53 16.5,45.53 16.5,44.53 17.5,44.53 19.5,44.53 18.5,44.53 17.5,46.53 33.15,71.48 19,14.03 17,14.03 18,14.03 18,13.03 15.53,25.53 27.15,86.1 5.25,81.18 5.25,78.58 6.35,68.18 5.88,76.6 18.45,91.63 11.1,72.83 35,30.85 34.75,22.05 34.75,20.65 34,35.03 34,36.03 33,37.03 30,37.03 34,37.03 33,35.03 30,35.03 33,36.03 30,36.03 31,36.03 31,35.03 34.05,44.73 33.05,45.73 34.05,45.73 33.05,44.73 30.05,44.73 31.05,44.73 20.5,44.53 20.5,24.53 20.5,25.53 21.5,25.53 21.5,24.53 20.5,34.53 20.5,35.53 21.5,35.53 21.5,34.53 34.5,16 34.75,17.8 30.27,17.03 31.27,17.03 19.48,88.28 55.38,42 57.42,48.88 11.53,62.38 37.65,91.18 42.6,67.53 45.55,54.45 40,64.63 31.05,45.73 30.05,45.73 3.4,42.98 3.4,40.98 3.4,38.98 3.4,34.98 3.4,32.98 3.4,30.98 3.4,27.98 3.4,25.98 3.4,23.98 42.8,19.33 44,36.03 44,35.03 44,33.03 43,32.03 43,33.03 43,35.03 43,36.03 44.25,19.28 44.25,20.28 44.25,21.28 44.25,22.28 41,2.03 39,2.03 37,2.03 35,2.03 33,2.03 31,2.03 29,2.03 25,2.03 23,2.03 21,2.03 19,2.03 17,2.03 43,2.03 34.05,47.73 11.88,57.5 20.32,54.4 43.65,77.28 40.65,77.23 50.02,77.25 17.2,69.08 3.48,47 49.05,47.45 42.95,48.65 44.9,48.65 53.9,69.9 56.3,63.75 14,79.63 19.32,54.4 31.68,55.05 29.88,55.05 56,38.03 56,37.03 56,36.03 57,36.03 57,37.03 57,38.03 56,29.03 57,29.03 13.53,60.38 33.08,88.05 18.5,46.53
  pour Bottom (isolate 0.254, rank 6): 0,0.03 0,111.03 60,111.03 60,0.03
  pour Top (rank 6): 0,49 0,111.03 60,111.03 60,49
  pour Top (no thermals): 16.15,24.53 19.5,24.53 19.5,27.73 16.15,27.73
  pour Top (isolate 0.254, rank 6): 0,49.13 60,49.13 60,0.03 0,0.03
  pour Top (no thermals): 16.15,15.53 19.5,15.53 19.5,17.73 16.15,17.73
  pour Top (no thermals): 16.15,34.53 19.5,34.53 19.5,37.83 16.15,37.83
  pour Top (no thermals): 16.15,44.53 19.5,44.53 19.5,47.73 16.15,47.73
  pour Top (no thermals): 17,9.6 17,4.28 20,4.28 20,9.6
  pour Bottom (no thermals): 17,9.6 17,4.28 20,4.28 20,9.6
  pour Top (no thermals): 41,14.5 43,14.5 43,11.03 41,11.03
  pour Top (no thermals): 53.42,15.13 49.42,15.13 49.42,11.13 53.42,11.13
  pour Bottom (no thermals): 53.42,15.13 49.42,15.13 49.42,11.13 53.42,11.13
  pour Bottom (no thermals): 53.45,40.05 49.45,40.05 49.45,36.05 53.45,36.05
  pour Top (isolate 0.5, no thermals): 53.45,40.05 49.45,40.05 49.45,36.05 53.45,36.05
  pour Top (no thermals): 22,105.03 20,105.03 20,102.68 22,102.68
  pour Bottom (no thermals): 22,105.03 20,105.03 20,102.68 22,102.68
  cutout Top: 9,44.93 11.1,44.93 11.55,45.38 11.55,46.88 11.25,47.18 9.3,47.18 9,46.88
  cutout Bottom: 8.75,25.78 13.55,25.78 14.25,26.48 14.25,28.28 12.45,28.28 12.45,26.18 9.15,26.18 9.15,28.28 10.8,29.93 10.8,43.13 9,44.78 9,44.48 10.5,42.98 10.5,30.08 8.75,28.33
  cutout Bottom: 15.45,48.98 15.45,51.23 18,53.78 23.55,53.78 23.55,53.63 18.15,53.63 15.6,51.08 15.6,48.98
GND1
  cutout Top: 9.2,26.23 11.3,26.23 11.45,26.38 11.45,28.48 9.5,28.48 9.2,28.18
GPIO0
  Top 0.152: JP8.1 42.28,81.18 U1.70
GPIO1
  Top 0.152: JP8.2 40.14,81.58 U1.71
GPIO2
  Top 0.152: JP8.3 42.4,83.84 36.93,83.84 36.09,83 35.66,83 35.44,82.78 U1.74
GPIO3
  Top 0.152: JP8.4 37.53,84.98 35.95,83.39 35.28,83.39 35.07,83.18 U1.75
GPIO4
  Top 0.152: JP8.5 42.27,86.25 38.24,86.25 35.77,83.78 34.9,83.78 34.7,83.58 U1.76
GPIO5
  Top 0.152: JP8.6 38.93,87.52 35.55,84.14 U1.1
GPIO6
  Top 0.152: JP8.7 42.4,88.92 39.13,88.92 36.02,85.81 32.68,85.81 32.02,85.15 U1.4
GPIO7
  Top 0.152: JP8.8 39.72,90.06 35.84,86.19 32.55,86.19 31.62,85.25 U1.5
HALL_UX
  Top 0.152: U1.38 26.57,74.38 26.29,74.1 19.43,74.1 17.34,72.01 16.59,72.01 16,71.43 U19.12
HALL_UX_5V  (via drill 0.3)
  Top 0.2: U19.13 16.65,70.12 15.26,68.73 13.2,68.73 12.6,68.13 v12.6,67.38
  Bottom 0.2: R40.1 C29.2 9.7,64.03 12.6,66.93 v12.6,67.38
HALL_V
  Top 0.152: U1.37 26.46,74.78 26.14,74.45 19.28,74.45 17.25,72.42 15.54,72.42 14.7,71.58 U19.10
HALL_V_5V  (via drill 0.3)
  Top 0.2: U19.11 15.35,70.21 14.42,69.28 12.45,69.28 v11.85,68.68
  Bottom 0.2: R41.1 C30.2 9.5,68.68 v11.85,68.68
HALL_WY
  Top 0.152: U1.36 26.36,75.18 26,74.81 19.13,74.81 17.1,72.78 14.89,72.78 13.4,71.28 U19.8
HALL_WY_5V  (via drill 0.3)
  Top 0.2: U19.9 14.05,70.08 13.8,69.83 12.3,69.83 v12.15,69.98
  Bottom 0.2: 9.11,72.43 C31.2 R42.1 11.8,70.33 v12.15,69.98
INPUT_GATE  (via drill 0.35)
  Top 0.5: v31.25,15.45 31.2,15.41 U22.4
  Bottom 0.5: U20.5 29.52,15.05 29.88,15.4 31.2,15.4 v31.25,15.45
MISO
  Top 0.152: X1.6 arc45 25.1,103.67 25.1,102.35 arc45 29.01,92.92 arc-45 30.02,90.47 U1.9
MOSI
  Top 0.152: U1.8 30.42,91.05 arc45 29.55,93.14 28.95,93.75 arc-45 26.52,99.62 26.52,102.93 26.52,103.43 X1.5
MOT_A  (via drill 0.35)
  Top 0.152: 21.69,49.99 v21.65,49.95
  Top 0.2: U8.3 21.69,49.99
  Top 0.254: v21.65,49.95 21.1,49.95 v20.8,49.65 | U5.6 31.97,51.23 31.84,51.1 v31.69,51.1
  Bottom 0.152: C22.2 31.69,51.91 v31.69,51.1
  Bottom 0.2: 22,49.78 21.82,49.95 v21.65,49.95
  Bottom 0.254: v20.8,49.65 20.93,49.78 22,49.78 23.98,49.78 D6.A 24.15,49.95 27.18,49.95 29.3,52.08 31.43,52.08 31.69,51.81 v31.69,51.1
  pour Top (isolate 0.305, no thermals): 22.8,53.23 22.8,49.33 21.5,49.33 20.75,48.58 15.85,48.58 15.85,53.23
  pour Top (isolate 0.305, no thermals): 12.9,48.88 18.7,48.88 18.7,51.13 16.62,53.2 12.9,53.2
MOT_A_OUT
  pour Top (isolate 0.305, no thermals): 5,47.5 5,44.03 5.45,43.58 9,43.58 9,46.58 11.4,48.98 12.18,48.98 12.18,53.1 10.6,53.1
MOT_B  (via drill 0.35)
  Top 0.152: U10.3 21.84,39.99 v21.77,39.93
  Top 0.254: v20.48,39.65 21.66,39.65 22,39.99 U10.3 | U4.6 31.97,41.23 31.84,41.1 v31.69,41.1
  Bottom 0.152: C21.2 31.69,41.91 v31.69,41.1
  Bottom 0.2: v21.77,39.93 22,39.7 22,39.65
  Bottom 0.254: v31.69,41.1 31.69,41.81 31.43,42.08 28.35,42.08 26,39.73 D7.A 23.93,39.65 22,39.65 v20.48,39.65
  pour Top (isolate 0.305, no thermals): 22.8,43.23 22.8,39.35 21.32,39.35 20.5,38.53 16.32,38.53 16.32,43.23
  pour Top (isolate 0.305, no thermals): 5,38.03 5,36.6 5.58,36.03 8.9,36.03 11.5,38.63 20,38.63 20,43.03 12.25,43.03 9.7,40.48 7.45,40.48
MOT_C  (via drill 0.35)
  Top 0.254: v20.1,29.65 20.44,29.99 v21.82,29.99 U12.3 | U3.6 31.97,31.23 31.84,31.1 v31.69,31.1
  Bottom 0.152: C20.2 31.69,31.91 v31.69,31.1
  Bottom 0.2: 22,29.8 21.82,29.98 v21.82,29.99
  Bottom 0.254: v20.1,29.65 20.25,29.8 22,29.8 D8.A 26.68,29.8 29.1,32.23 31.27,32.23 31.69,31.81 v31.69,31.1
  pour Top (isolate 0.305, no thermals): 22.77,33.4 22.77,29.33 21.3,29.33 20.5,28.53 16.3,28.53 16.3,33.4
  pour Top (isolate 0.305, no thermals): 12.97,33.88 15.35,33.88 15.88,33.35 16.32,33.35 16.52,33.15 17.45,33.15 17.45,29.55 13.97,29.55 12.97,30.55
MOT_C_OUT
  pour Top (isolate 0.305, no thermals): 12.22,33.8 12.22,31.05 9.55,28.38 5.6,28.38 5,28.98 5,30.03 6.75,31.78 7.97,31.78 9.81,33.8
MOT_D  (via drill 0.35)
  Top 0.254: v20.07,19.2 20.61,19.74 v21.27,19.74 21.95,19.74 U15.3 | U2.6 31.97,21.23 31.84,21.1 v31.69,21.1
  Bottom 0.152: C19.2 31.69,21.91 v31.69,21.1
  Bottom 0.2: 22,19.45 21.71,19.74 v21.27,19.74
  Bottom 0.254: v20.07,19.2 20.32,19.45 22,19.45 D11.A 25.75,19.45 28.5,22.2 31.3,22.2 31.69,21.81 v31.69,21.1
  pour Top (isolate 0.305, no thermals): 22.8,23.23 22.8,19.4 21.38,19.4 20.6,18.63 16.5,18.63 16.5,23.23
  pour Top (isolate 0.305, no thermals): 21,19.03 6,19.03 5,20.03 5,22.53 5.75,23.28 21,23.28
N$1
  Top 0.2: R36.1 7.9,68.23 3.6,63.93 3.06,63.93 JP12.4
  Bottom 0.2: R40.2 5.29,63.99 JP12.4
N$3
  Top 0.2: R38.1 5.4,69.33 5.4,67.73 4.2,66.53 JP12.3
  Bottom 0.2: R41.2 3.4,66.13 JP12.3
N$4  (via drill 0.3)
  Top 0.152: v28.5,87.33 28.82,87.01 U1.12
  Top 0.2: D1.A 34.9,87.68 v34.98,87.6
  Bottom 0.2: v34.98,87.6 34.04,86.66 29.16,86.66 v28.5,87.33
N$5  (via drill 0.35)
  Top 0.2: v44.15,54.7 44.15,55.55 U24.3 42.58,55.85 R45.1
  Bottom 0.2: R46.2 44.15,54.95 v44.15,54.7
N$8
  Top 0.2: R29.1 53.52,71.7 56.2,69.03 LED1.A
N$12
  Top 0.5: D16.A 39.76,61.53
  Top 0.75: U24.1 44.45,58.8 43.17,60.08 43.17,60.8 L2.2
  Top 1: L2.2 42.45,61.53 39.76,61.53
N$13
  Top 0.254: U5.5 31.52,52.03 R11.2
N$15  (via drill 0.3)
  Top 0.2: R39.1 6.2,72.23 6.2,71.93 | v6.2,71.73 6.2,71.93 | 6.2,71.93 3.34,69.07 JP12.2
  Bottom 0.2: R42.2 6.35,71.33 6.35,71.58 v6.2,71.73
N$16  (via drill 0.35)
  Top 0.5: 49.2,44.9 49.23,44.92 U23.8 50.13,44.32 v50.8,43.65
  Top 0.8: 45.95,45.65 L1.1 | 46.7,44.9 46.63,44.97 45.95,45.65 | 45.95,45.65 45.67,45.93
  Top 1: 49.2,44.9 46.7,44.9 | D14.C 44.84,45.1 45.67,45.93
  Bottom 0.2: C36.2 51.6,42.85
  Bottom 0.254: v50.8,43.65 51.6,42.85
N$17
  Top 0.2: X1.16 38.89,106.14 40.35,104.68 40.35,102.38 39.05,101.08 R22.2
N$18  (via drill 0.35)
  Top 0.254: v32.65,48.78 32.65,49.57 32.71,49.63 U5.8
  Bottom 0.152: C22.1 33.33,52.08
  Bottom 0.25: v32.65,48.78 33.15,48.78 33.7,49.33 D5.C
  Bottom 0.254: 33.33,52.08 33.52,51.88 33.52,49.66 D5.C
N$19  (via drill 0.35)
  Top 0.2: U23.1 56.16,44.92
  Top 0.254: v56.38,44.55 56.38,44.7 56.16,44.92
  Bottom 0.254: v56.38,44.55 54.67,42.85 C36.1
N$20
  Top 0.5: SJ6.1 22.38,99.69 22.38,104.5 23.65,105.78 X1.4
N$21  (via drill 0.35)
  Top 0.2: 50.11,48.75 U23.5
  Top 0.254: 50.11,48.75 49.15,48.75 v49.05,48.85
  Bottom 0.2: R44.1 53.55,49.3 51.73,49.3 51.75,49.28 R43.1 51.55,48.73
  Bottom 0.254: 51.55,48.73 49.17,48.73 v49.05,48.85
N$23
  Top 1: X1.2 20.71,106.7 13.35,106.7 JP5.1
N$24
  Bottom 0.152: C33.1 25.25,12.08
  Bottom 0.5: U20.1 25.55,14.1 25.55,12.38 25.25,12.08
N$25  (via drill 0.35)
  Top 0.2: 56.42,46.12 56.4,46.09 | 55.67,46.09 U23.2
  Top 0.254: v56.42,46.2 56.42,46.12 | 56.4,46.09 55.67,46.09
  Bottom 0.254: C35.2 54.6,44.93 55.77,46.1 56.33,46.1 v56.42,46.2
N$27
  Top 0.254: U5.7 32.2,50.43 R10.2
N$28  (via drill 0.35)
  Top 0.254: U4.8 32.65,39.22 v32.65,38.78
  Bottom 0.152: C21.1 33.33,42.08
  Bottom 0.254: v32.65,38.78 33.33,39.45 33.45,39.45
  Bottom 0.3: 33.33,42.08 33.35,42.05 33.35,39.55 33.45,39.45 33.58,39.33 D4.C
N$29
  Top 0.254: U4.5 31.52,42.03 R9.2
N$30
  Top 0.254: U4.7 32.2,40.43 R8.2
N$31  (via drill 0.35)
  Top 0.254: v32.65,18.78 32.65,19.57 32.71,19.63 U2.8
  Bottom 0.152: C19.1 33.33,22.08
  Bottom 0.254: v32.65,18.78 33.2,19.33 D2.C
  Bottom 0.3: 33.33,22.08 33.55,21.85 33.55,19.33 D2.C
N$32
  Top 0.254: U2.5 31.52,22.03 R5.2
N$33
  Top 0.254: U2.7 32.2,20.43 R4.2
N$34  (via drill 0.35)
  Top 0.254: v32.65,28.78 32.65,29.57 32.71,29.63 U3.8
  Bottom 0.152: C20.1 33.33,32.08
  Bottom 0.254: v32.65,28.78 33.2,29.33 D3.C
  Bottom 0.3: 33.33,32.08 33.48,31.93 33.48,29.33 D3.C
N$35
  Top 0.254: U3.5 31.52,32.03 R7.2
N$36
  Top 0.254: U3.7 32.2,30.43 R6.2
PWM_I
  Top 0.152: JP10.1 56.31,76.38 U1.58
REF_H
  Top 0.152: JP9.3 56.23,84.29 56.23,86.27 55.31,87.19 54.07,87.19 47.26,80.38 U1.68
REF_L
  Top 0.152: JP9.1 55.8,82.18 55.8,86.19 55.16,86.83 54.26,86.83 47.4,79.98 U1.67
REF_R
  Top 0.152: JP9.5 55.52,87.54 53.81,87.54 47.04,80.78 U1.69
RES_FET  (via drill 0.35)
  Top 0.254: v39,15.03 37.83,13.85 U17.5
  Bottom 0.254: D12.A 41,15.25
  Bottom 0.305: 41,15.25 39.23,15.25 v39,15.03
  Bottom 1: D13.C 42.21,8.98 41.43,8.19 X2.4
  pour Top (isolate 0.305, no thermals): 42.5,9.03 42.5,5.53 42,5.03 41.02,5.03 35.75,10.3 35.75,15.6 40,15.6 40,11.03 42,9.03
RESET  (via drill 0.3)
  Top 0.152: U1.50 32.4,73.78 32.4,69.19 v32.66,68.93
  Top 0.2: X1.3 23.32,103.43 23.32,90.08 v23.3,90.05 | v20.32,72.13 20.5,72.13 20.5,68.93 v20.4,68.93
  Bottom 0.152: R2.1 28.38,68.93 v20.4,68.93
  Bottom 0.2: v32.66,68.93 32.34,69.25 28.7,69.25 R2.1 | v20.32,72.13 20.32,72.73 21.07,73.48 21.07,84.53 21.4,84.85 21.4,88.23 23.23,90.05 v23.3,90.05
SCK
  Top 0.152: U1.7 30.82,91.02 arc45 29.7,93.73 29.36,94.07 arc-45 27.57,98.37 27.57,105.07 arc-45 27.79,105.58 28.5,106.3 X1.8
SENSE_A  (via drill 0.3, 0.35)
  Top 0.152: v25.2,84.98 25.2,84.61 26.64,83.18 U1.16
  Top 0.2: v23.94,71.65 23.85,71.56 23.85,61.84 22.54,60.53 v21.94,60.53
  Top 0.254: U6.7 13.13,47.56 v13.2,47.63
  Bottom 0.2: v23.94,71.65 23.94,72.01 23.89,72.05 23.89,72.6 24.05,72.75 24.05,83.67 25.2,84.83 v25.2,84.98 25.2,86.48 C27.2 | v13.2,47.63 13.2,51.64 21.94,60.38 v21.94,60.53
SENSE_C  (via drill 0.3, 0.35)
  Top 0.152: U1.18 25.9,82.38 24.45,83.83 23.84,83.83 v23.11,84.55
  Top 0.2: 13.19,28.71 v13.2,28.73 | v19.74,60.53 22.63,63.42 v22.63,71.33
  Top 0.254: U7.7 13.19,28.71
  Bottom 0.2: v13.2,28.73 12.75,29.18 12.75,45.57 10.76,47.57 10.76,47.67 12.35,49.26 12.35,52.29 19.74,59.69 v19.74,60.53 | v22.63,71.33 22.58,71.38 22.58,72.5 23.11,73.03 v23.11,84.55 23.11,86.49 C28.2
STEP
  Top 0.152: JP10.2 55.55,75.98 U1.57
TH_FET  (via drill 0.3)
  Top 0.2: U18.3 v21,65.33 | v27.61,57.24 27.75,57.38 v30.15,57.38
  Bottom 0.2: v21,65.33 21.3,65.03 22.8,65.03 26.35,61.48 26.35,58.5 v27.61,57.24 | R30.1 26.8,33.38 34.8,33.38 35.7,34.28 35.7,56.23 34.6,57.33 R31.2 30.2,57.33 v30.15,57.38
UART_RX  (via drill 0.3)
  Top 0.152: U1.10 29.62,90.15 arc45 28.84,92.04 26.65,94.23 v25.15,94.23
  Top 0.2: JP6.1 56.38,97.95 v45.12,97.95
  Bottom 0.2: v25.15,94.23 28.88,97.95 v45.12,97.95
UART_TX  (via drill 0.3)
  Top 0.152: U1.11 29.22,89.91 arc45 28.55,91.52 26.85,93.23 v25.15,93.23
  Top 0.2: JP6.2 54.77,97.03 v44,97.03
  Bottom 0.2: v44,97.03 43.77,97.26 29.18,97.26 v25.15,93.23
V+  (via drill 0.35)
  Top 0.4: U23.7 49.06,46.19 v49.02,46.23
  Top 0.5: v27.88,16.73 27.8,16.65 27.8,14.88 U22.5
  Top 0.8: C10.+ 54.12,33.09 54.12,39.3 52.12,41.3 52.12,45.12 51.05,46.19 U23.7
  Bottom 0.2: R43.2 51.2,46.48 | v49.02,46.23 47.9,46.23 47.08,47.05 47.08,68.13 48,69.05 R25.2 | R23.2 24.4,52.1 C11.1
  Bottom 0.254: 51.2,46.48 49.27,46.48 v49.02,46.23
  Bottom 0.305: v41.17,24 41.17,18.99 D12.C
  Bottom 0.5: v27.88,16.73 U20.4 | v49.02,46.23 49.02,45.98 C37.2
  other vias: 24.9,22.18 24.9,21.38 24.2,21.08 24.2,22.48 24.88,32.45 24.88,31.65 24.18,31.35 24.18,32.75 24.9,42.28 24.9,41.48 24.2,41.18 24.2,42.58 24.93,52.48 24.93,51.68 24.23,51.38 24.23,52.78
  pour Bottom (isolate 0.305, no thermals): 23.73,51.18 23.73,52.98 25.23,52.98 25.23,51.18
  pour Bottom (isolate 0.305, no thermals): 23.7,20.73 23.7,22.8 25.2,22.8 25.2,20.73
  pour Bottom (isolate 0.305, no thermals): 23.68,31.15 23.68,32.95 25.18,32.95 25.18,31.15
  pour Bottom (isolate 0.305, no thermals): 23.7,40.98 23.7,42.78 25.2,42.78 25.2,40.98
  pour Top (isolate 0.5, no thermals): 23.27,53.18 29,53.18 29,7.03 27,5.03 25.48,5.03 23.27,7.23
  pour Top (isolate 0.4, no thermals): 53.42,20.55 53.42,30.73 52.17,31.98 50.67,31.98 49.42,30.73 49.42,28.13 28,28.13 28,23.48 49.42,23.48 49.42,20.6 50.67,19.35 52.23,19.35
V_EXT  (via drill 0.3)
  Top 0.2: X1.13 36.35,103.25 37.1,102.5 37.1,92.95 37.92,92.13 45.9,92.13 v46.17,91.85
  Bottom 0.2: 45.73,73.3 45.5,73.08 45.45,73.08 | 45.73,73.3 46.4,73.98 46.4,91.63 v46.17,91.85 | R27.1 45.45,73.08 | 45.45,73.08 R28.2 45.58,73.3 45.73,73.3
V_GD  (via drill 0.35)
  Top 0.2: R45.2 41.75,56.93
  Top 0.254: U5.1 36.97,49.65 v38.17,49.65 38.08,49.65 37.98,49.55 C8.2 | U4.1 v38.15,39.63 38.17,39.65 C7.2 | U3.1 v38.15,29.63 38.2,29.58 C6.2 | U2.1 v38.15,19.63 38.15,20 39.52,21.38 C5.2
  Top 0.3: U14.2 40.67,21.1 C5.2
  Top 0.5: 37,58.3 C39.1 37.12,58.33 | 41.75,56.93 40.44,58.24 D16.C 39.69,58.18
  Top 1: 39.69,58.18 39.54,58.33 37.12,58.33 | JP4.1 34.65,58.3 37,58.3
  Bottom 0.2: D5.A 37.08,49.27
  Bottom 0.254: v38.17,49.65 37.85,49.33 D5.A | v38.15,39.63 37.85,39.33 D4.A | v38.15,29.63 37.85,29.33 D3.A | v38.15,19.63 37.85,19.33 D2.A
  Bottom 1: D2.A 37.17,19.33 37.17,29.33 D3.A 37.14,29.63 D4.A 37.17,39.36 37.17,49.18 37.08,49.27 37.02,49.33 37.02,57.01 33.95,60.08 JP4.1
V_INT  (via drill 0.3)
  Top 0.2: X1.14 37.6,105.05 37.6,93.03 37.98,92.65 46.84,92.65 v46.93,92.55
  Bottom 0.2: v46.93,92.55 47.05,92.43 47.05,74 48,73.05 R26.2 R25.1
V_INT_TMC  (via drill 0.3)
  Top 0.152: v24.55,72.33 24.57,72.33 24.57,67.76 24.3,67.48 24.3,65.33 | U1.20 25.2,81.58 v24.93,81.85 | U18.12 24.3,65.33 | 24.3,65.33 24.3,63.68 24.6,63.38 U18.9 U18.8
  Bottom 0.152: v24.93,81.85 24.43,81.35 24.43,72.6 24.55,72.48 v24.55,72.33
V_INT_TMC_RAW  (via drill 0.3)
  Top 0.2: v24.05,60.78 24.55,60.78 26.1,62.33 26.1,63.83 25.9,64.03 U18.10
  Bottom 0.2: R24.2 24.3,56.18 R23.1 24.4,60.43 v24.05,60.78
V_MOT_IN  (via drill 0.35)
  Bottom 0.152: C33.2 27.15,12.08
  Bottom 0.2: U20.3 26.02,16 26.52,15.5 26.52,14.36 26.78,14.1 U20.6 | R27.2 46.35,68.18 46.35,32.93 40.43,27.01 40.43,20.86 39.96,20.38 39.96,19.09 37.74,16.88 33.94,16.88 31.38,14.32 30.89,14.32 v30.43,13.85
  Bottom 0.5: v30.43,13.85 30.18,14.1 U20.6 27.53,14.1 27.53,12.46 27.15,12.08
  other vias: 30.43,12.85 32.42,12.85 31.43,12.85 30.43,11.85
  pour Top (isolate 0.4, no thermals): 29.7,14.5 29.7,6.23 30.9,5.03 34.38,5.03 34.8,5.45 34.8,8.6 34,9.4 34,12.1 31.6,14.5
  pour Bottom (isolate 0.4, no thermals): 29.7,14.5 29.7,6.23 30.9,5.03 34.38,5.03 34.8,5.45 34.8,11.3 31.6,14.5
VCORE  (via drill 0.3)
  Top 0.152: v30.15,71.71 30.15,71.78 30.42,72.05 U1.45 | U1.15 27.04,83.58 26.87,83.75 v26.87,84.93 | v35.48,78.13 35.23,78.38 U1.63
  Bottom 0.152: C3.2 26.87,84.41 v26.87,84.93 | v35.48,78.13 35.48,78.7 C4.2
  Bottom 0.2: v30.15,71.71 30.15,71.78 C1.2 30.93,72.8 30.3,73.43 30.3,75.88 29.4,76.78 27.43,76.78 26.77,77.43 26.77,83.33 27.07,83.63 C3.2 30.77,80.5 34.08,80.5 35.02,79.55 C4.2

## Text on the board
tPlace: 5V | E-Stop | EN | GND | 3V3 | P | N | 2.5V -> N / (Single ended) | V | AENC | RX | U|X | TX | W|Y | GND | 5V | 7 | 6 | UART (3V3) | 3V3 | 2V5 / N Offset | GND | 4 | 5 | 5V | R | GPIO | 3 | 2 | Z | AGPI_A | Z | 0 | B | H | ENC | 1 | ENO | L | B | ENC2 (3V3) | A | TMC4671 | A | PWM | GND | STP | 5V | DIR | WY | V | HALL | UX | PWR | GND | + | 5V | 10V | A | MOTOR | B | C | D | 3 phase / ABC = UVW | MOTOR / A|B|C|D | GND | PB+ | VM | PB- | Power | SUPPLY / 1:GND / 2:PB+ / 3:VM + / 4:PB-
bPlace: 5V | E-Stop | 16 | 2 | 1 | GND | 5V | RST | 3V3 | MOSI | MISO | CS1 | SCK | CS2 | CS3 | FLAG | BRK | V_EXT | V_INT | NC | ENABLE | EN | GND | P | N | V | RX | UART | U | TX | Cos | 1 | 2 | 3 | AENC | GND | W | Sin | N/CM | 2V5 | 3V3 | 5V | N Offset | SPI ADDR | 5V | GND | ENC2 (3V3) | Z | R | 5V | B | H | Z | A | L | B | PWM | A | ENCODER | VEXT | VINT | STP | GND | DIR | 5V | WY | V | HALL | BR_TH | UX | 2V5-REF / Sense | 5V | V_GD / (10V) | GND | STEPPER: AB(A) CD(B) | 3 PHASE: ABC(UVW) | DC: AB | Open FFBoard - TMC4671 Motor driver | A | B | TMP | MOTOR | C | D | V1.3 - YR 2021 | Supply: / PSU (protected): VM (+) and GND (-) / ALWAYS connect braking resistor / between PB+ (Internal motor supply) and PB- | R | VM | GND | PB+ | PB- | - | + | Power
